VERSION 5.8 ;
BUSBITCHARS "[]" ;
DIVIDERCHAR "/" ;
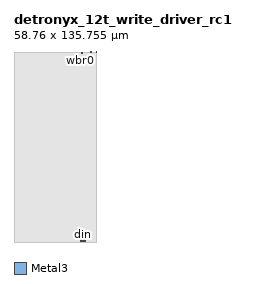
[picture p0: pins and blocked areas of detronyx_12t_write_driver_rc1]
MACRO detronyx_12t_write_driver_rc1
  CLASS BLOCK ;
  FOREIGN detronyx_12t_write_driver_rc1 0.000 0.000 ;
  ORIGIN 0.000 0.000 ;
  SIZE 58.760000 BY 135.755000 ;
  SYMMETRY X Y ;
  PIN VDD
    DIRECTION INOUT ;
    USE POWER ;
    PORT
      LAYER Metal3 ;
        RECT 48.380000 134.555000 48.740000 135.755000 ;
    END
  END VDD
  PIN VSS
    DIRECTION INOUT ;
    USE GROUND ;
    PORT
      LAYER Metal3 ;
        RECT 47.680000 0.700000 48.040000 1.900000 ;
    END
  END VSS
  PIN din
    DIRECTION INPUT ;
    USE SIGNAL ;
    PORT
      LAYER Metal3 ;
        RECT 49.080000 0.700000 49.440000 1.500000 ;
    END
  END din
  PIN wen
    DIRECTION INPUT ;
    USE SIGNAL ;
    PORT
      LAYER Metal3 ;
        RECT 58.880000 135.655000 59.240000 136.455000 ;
    END
  END wen
  PIN wbl0
    DIRECTION INPUT ;
    USE SIGNAL ;
    PORT
      LAYER Metal3 ;
        RECT 50.480000 0.700000 50.840000 1.500000 ;
    END
  END wbl0
  PIN wbr0
    DIRECTION INPUT ;
    USE SIGNAL ;
    PORT
      LAYER Metal3 ;
        RECT 54.680000 135.655000 55.040000 136.455000 ;
    END
  END wbr0
  OBS
    LAYER Metal1 ;
      RECT 0.000000 0.000000 58.760000 135.755000 ;
    LAYER Metal2 ;
      RECT 0.000000 0.000000 58.760000 135.755000 ;
  END
END detronyx_12t_write_driver_rc1
END LIBRARY
